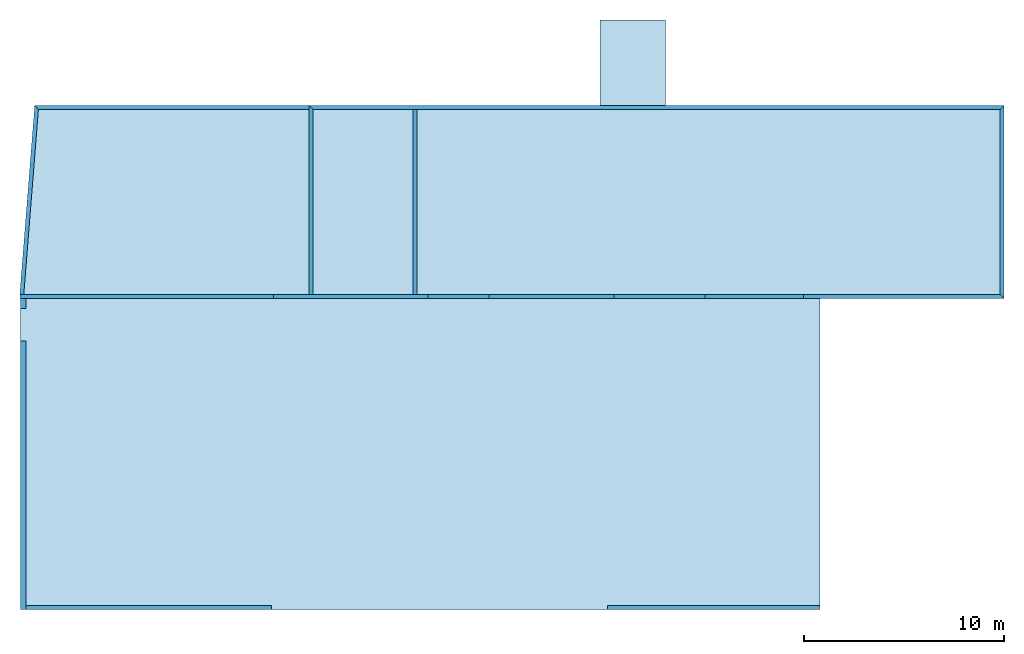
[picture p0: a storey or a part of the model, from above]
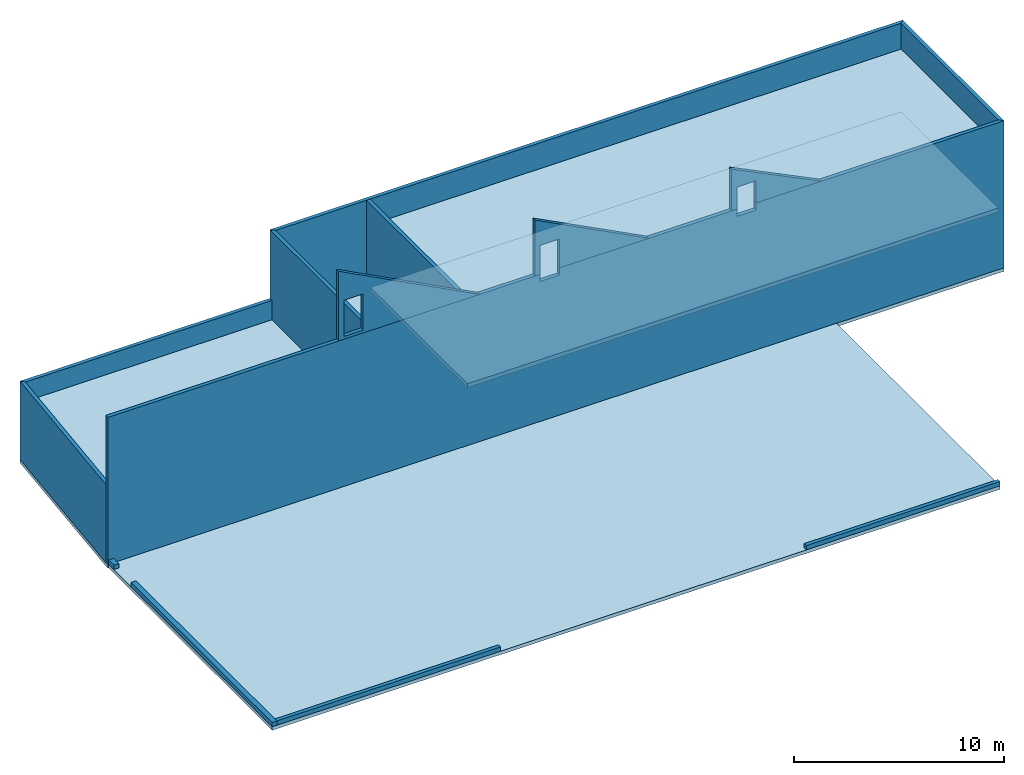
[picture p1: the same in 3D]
Properties of the parts of a building model (IFC2X3)

# File
Description: ViewDefinition[CoordinationView_V2.0, QuantityTakeOffAddOnView]
File name: PoleAeroBati.ifc
Time: 2018-09-14T00:26:13
Author: PORTCM01\professeur
Organization: Structural Designer
Written by: IFC Database version:Work
Made in: Tekla Structures Educational 2017 Service Pack 2, IFC Export Version: 4.0.0.0 May 16 2017

# IfcSite, Undefined
RefElevation: 0 mm

# IfcBuildingStorey, Undefined
In: Undefined
Elevation: 0 mm

# IfcBeam: 250*200 (2)
In: Undefined
Description: 250*200; Material: CONCRETE/C25/30
Tekla Commun - Phase: 1; Profil: 250*200; Nom: POUTRE; sets with these values: 2
Tekla Quantités - Surface par tonne: 7.6 m2; Hauteur: 250 mm; Largeur: 200 mm; sets with these values: 2
Pset_BeamCommon - LoadBearing: yes
Name | Repère de pièce = Repère d'assemblage = Reference | Poids (kg) = NetWeight (kg) | Volume (m3) | Surface supérieure totale (m2) | Surface nette (m2) | Longueur (mm) = Length (mm) | OuterSurfaceArea (m2) | NetVolume (m3)
POUTRE | Po9 | 1277.4 | 0.5 | 2.1 | 9.7 | 10645 | 9.6805 | 0.53225
POUTRE | Po8 | 1474.8 | 0.6 | 2.5 | 11.2 | 12290 | 11.161 | 0.6145

# IfcBeam: 250*270 (2)
In: Undefined
Description: 250*270; Material: CONCRETE/C25/30
Tekla Commun - Phase: 1; Profil: 250*270; Nom: POUTRE; sets with these values: 2
Tekla Quantités - Hauteur: 250 mm; Largeur: 270 mm; sets with these values: 2
Pset_BeamCommon - LoadBearing: yes
Name | Repère de pièce = Repère d'assemblage = Reference | Poids (kg) | Volume (m3) | Surface supérieure totale (m2) | Surface par tonne (m2) | Surface nette (m2) | Longueur (mm) = Length (mm) | OuterSurfaceArea (m2) | NetVolume (m3) | NetWeight (kg)
POUTRE | Po11 | 2174.9 | 0.9 | 3.6 | 6.5 | 14.1 | 13425 | 14.097 | 0.906188 | 2174.85
POUTRE | Po10 | 81 | 0 | 0.1 | 8.1 | 0.7 | 500 | 0.655 | 0.03375 | 81

# IfcBeam: 4550*200 (2)
In: Undefined
Description: 4550*200; Material: CONCRETE/C25/30
Tekla Commun - Phase: 1; Profil: 4550*200; Nom: POUTRE; sets with these values: 2
Tekla Quantités - Surface par tonne: 4.4 m2; Hauteur: 4550 mm; Largeur: 200 mm; sets with these values: 2
Pset_BeamCommon - LoadBearing: yes
Name | Repère de pièce = Repère d'assemblage = Reference | Poids (kg) = NetWeight (kg) | Volume (m3) | Surface supérieure totale (m2) | Surface nette (m2) | Longueur (mm) | Length (mm) | OuterSurfaceArea (m2) | NetVolume (m3)
POUTRE | Po5 | 29791.9 | 12.4 | 2.7 | 131.7 | 13733.4 | 13733.4 | 131.739 | 12.4133
POUTRE | Po4 | 20476.6 | 8.5 | 1.9 | 91.2 | 9478.7 | 9478.66 | 91.2034 | 8.53192

# IfcBeam: 8550*200 (5)
In: Undefined
Description: 8550*200; Material: CONCRETE/C25/30
Tekla Commun - Phase: 1; Profil: 8550*200; Nom: POUTRE; sets with these values: 2
Tekla Quantités - Hauteur: 8550 mm; Largeur: 200 mm; sets with these values: 2
Pset_BeamCommon - LoadBearing: yes
Name | Repère de pièce = Repère d'assemblage = Reference | Poids (kg) = NetWeight (kg) | Volume (m3) | Surface supérieure totale (m2) | Surface par tonne (m2) | Surface nette (m2) | Longueur (mm) = Length (mm) | OuterSurfaceArea (m2) | NetVolume (m3)
POUTRE | Po7 | 37962 | 15.8 | 1.9 | 4.4 | 165.3 | 9250 | 165.295 | 15.8175
POUTRE | Po6 | 38372.4 | 16 | 1.9 | 4.4 | 167.8 | 9450 | 167.753 | 15.9885
POUTRE | Po3 | 124128 | 51.7 | 6.9 | 4.4 | 547.8 | 34778 | 547.813 | 51.7201
POUTRE | Po2 | 38782.8 | 16.2 | 1.9 | 4.4 | 170.2 | 9650 | 170.212 | 16.1595
POUTRE | Po1 | 201274 | 83.9 | 9.4 | 4.2 | 862.8 | 49248 | 862.765 | 83.8642

# IfcElementAssembly (20)
In: Undefined
PredefinedType: REINFORCEMENT_UNIT
Tekla Assemblages - Poids ferraillage Elément béton: 0 kg; sets with these values: 2
Name | Poids Assemblage/Elément béton (kg) | Nom Assemblage/Elément béton | Repère Assemblage/Elément béton | Width (mm)
DALLE | 22200 | DALLE | Da8 | 200
POUTRE | 2174.85 | POUTRE | Po11 | 270
POUTRE | 1277.4 | POUTRE | Po9 | 200
POUTRE | 1474.8 | POUTRE | Po8 | 200
POUTRE | 81 | POUTRE | Po10 | 270
DALLE | 298981 | DALLE | Da7 | 200
DALLE | 2217.26 | DALLE | Da3 | 200
DALLE | 4030.23 | DALLE | Da2 | 200
DALLE | 6459.18 | DALLE | Da1 | 200
DALLE | 233208 | DALLE | Da6 | 200
DALLE | 148983 | DALLE | Da9 | 230
POUTRE | 37962 | POUTRE | Po7 | 200
POUTRE | 38372.4 | POUTRE | Po6 | 200
POUTRE | 29791.9 | POUTRE | Po5 | 200
DALLE | 142505 | DALLE | Da5 | 220
DALLE | 71045.8 | DALLE | Da4 | 230
POUTRE | 20476.6 | POUTRE | Po4 | 200
POUTRE | 124128 | POUTRE | Po3 | 200
POUTRE | 38782.8 | POUTRE | Po2 | 200
POUTRE | 201274 | POUTRE | Po1 | 200

# IfcSlab: 200*13930, DALLE
In: Undefined
Description: 200*13930; PredefinedType: FLOOR; Material: CONCRETE/C25/30
Tekla Commun - Repère de pièce: Da6; Repère d'assemblage: Da6; Phase: 1; Profil: 200*13930; Nom: DALLE; sets with these values: 2
Tekla Quantités - Poids: 233208 kg; Volume: 97.2 m3; Surface supérieure totale: 485.8 m2; Surface par tonne: 4.2 m2; Surface nette: 996.8 m2; Hauteur: 13930 mm; Largeur: 200 mm; Longueur: 49248 mm; sets with these values: 2
Pset_SlabCommon - LoadBearing: yes; Reference: Da6
BaseQuantities - Width: 200 mm; NetVolume: 97.1699 m3; NetArea: 485.85 m2; NetWeight: 233208 kg

# IfcSlab: 200*15570, DALLE
In: Undefined
Description: 200*15570; PredefinedType: FLOOR; Material: CONCRETE/C25/30
Tekla Commun - Repère de pièce: Da7; Repère d'assemblage: Da7; Phase: 1; Profil: 200*15570; Nom: DALLE; sets with these values: 2
Tekla Quantités - Poids: 298981 kg; Volume: 124.6 m3; Surface supérieure totale: 622.9 m2; Surface par tonne: 4.2 m2; Surface nette: 1268 m2; Hauteur: 15570 mm; Largeur: 200 mm; Longueur: 40005 mm; sets with these values: 2
Pset_SlabCommon - LoadBearing: yes; Reference: Da7
BaseQuantities - Width: 200 mm; NetVolume: 124.576 m3; NetArea: 622.878 m2; NetWeight: 298981 kg

# IfcSlab: 200*2425, DALLE
In: Undefined
Description: 200*2425; PredefinedType: FLOOR; Material: CONCRETE/C25/30
Tekla Commun - Repère de pièce: Da3; Repère d'assemblage: Da3; Phase: 1; Profil: 200*2425; Nom: DALLE; sets with these values: 2
Tekla Quantités - Poids: 2217.3 kg; Volume: 0.9 m3; Surface supérieure totale: 0 m2; Surface par tonne: 5.6 m2; Surface nette: 12.3 m2; Hauteur: 2425.4 mm; Largeur: 200 mm; Longueur: 4933.1 mm; sets with these values: 2
Pset_SlabCommon - LoadBearing: yes; Reference: Da3
BaseQuantities - Width: 200 mm; NetVolume: 0.923859 m3; NetArea: 0 m2; NetWeight: 2217.26 kg

# IfcSlab: 200*3249, DALLE
In: Undefined
Description: 200*3249; PredefinedType: FLOOR; Material: CONCRETE/C25/30
Tekla Commun - Repère de pièce: Da2; Repère d'assemblage: Da2; Phase: 1; Profil: 200*3249; Nom: DALLE; sets with these values: 2
Tekla Quantités - Poids: 4030.2 kg; Volume: 1.7 m3; Surface supérieure totale: 0 m2; Surface par tonne: 5.2 m2; Surface nette: 20.8 m2; Hauteur: 3249 mm; Largeur: 200 mm; Longueur: 6269.9 mm; sets with these values: 2
Pset_SlabCommon - LoadBearing: yes; Reference: Da2
BaseQuantities - Width: 200 mm; NetVolume: 1.67926 m3; NetArea: 0 m2; NetWeight: 4030.23 kg

# IfcSlab: 200*4052, DALLE
In: Undefined
Description: 200*4052; PredefinedType: FLOOR; Material: CONCRETE/C25/30
Tekla Commun - Repère de pièce: Da1; Repère d'assemblage: Da1; Phase: 1; Profil: 200*4052; Nom: DALLE; sets with these values: 2
Tekla Quantités - Poids: 6459.2 kg; Volume: 2.7 m3; Surface supérieure totale: 0 m2; Surface par tonne: 5 m2; Surface nette: 32.3 m2; Hauteur: 4052 mm; Largeur: 200 mm; Longueur: 7745.8 mm; sets with these values: 2
Pset_SlabCommon - LoadBearing: yes; Reference: Da1
BaseQuantities - Width: 200 mm; NetVolume: 2.69133 m3; NetArea: 0 m2; NetWeight: 6459.18 kg

# IfcSlab: 200*5000, DALLE
In: Undefined
Description: 200*5000; PredefinedType: FLOOR; Material: CONCRETE/C25/30
Tekla Commun - Repère de pièce: Da8; Repère d'assemblage: Da8; Phase: 1; Profil: 200*5000; Nom: DALLE; sets with these values: 2
Tekla Quantités - Poids: 22200 kg; Volume: 9.2 m3; Surface supérieure totale: 46.2 m2; Surface par tonne: 4.4 m2; Surface nette: 98.2 m2; Hauteur: 5000 mm; Largeur: 200 mm; Longueur: 9250 mm; sets with these values: 2
Pset_SlabCommon - LoadBearing: yes; Reference: Da8
BaseQuantities - Width: 200 mm; NetVolume: 9.25 m3; NetArea: 46.25 m2; NetWeight: 22200 kg

# IfcSlab: 220*9250, DALLE
In: Undefined
Description: 220*9250; PredefinedType: FLOOR; Material: CONCRETE/C25/30
Tekla Commun - Repère de pièce: Da5; Repère d'assemblage: Da5; Phase: 1; Profil: 220*9250; Nom: DALLE; sets with these values: 2
Tekla Quantités - Poids: 142505 kg; Volume: 59.4 m3; Surface supérieure totale: 269.9 m2; Surface par tonne: 3.9 m2; Surface nette: 556.7 m2; Hauteur: 9250 mm; Largeur: 220 mm; Longueur: 29178 mm; sets with these values: 2
Pset_SlabCommon - LoadBearing: yes; Reference: Da5
BaseQuantities - Width: 220 mm; NetVolume: 59.3772 m3; NetArea: 269.897 m2; NetWeight: 142505 kg

# IfcSlab: 230*9250 (2)
In: Undefined
Description: 230*9250; PredefinedType: FLOOR; Material: CONCRETE/C25/30
Tekla Commun - Phase: 1; Profil: 230*9250; Nom: DALLE; sets with these values: 2
Tekla Quantités - Hauteur: 9250 mm; Largeur: 230 mm; sets with these values: 2
Pset_SlabCommon - LoadBearing: yes
BaseQuantities - Width: 230 mm
Name | Repère de pièce = Repère d'assemblage = Reference | Poids (kg) = NetWeight (kg) | Volume (m3) | Surface supérieure totale (m2) | Surface par tonne (m2) | Surface nette (m2) | Longueur (mm) | NetVolume (m3) | NetArea (m2)
DALLE | Da9 | 148983 | 62.1 | 269.9 | 3.7 | 557.5 | 29178 | 62.0762 | 269.897
DALLE | Da4 | 71045.8 | 29.6 | 128.7 | 3.8 | 268.1 | 14279.8 | 29.6024 | 128.706
